VERSION 5.8 ;
BUSBITCHARS "[]" ;
DIVIDERCHAR "/" ;

PROPERTYDEFINITIONS
  MACRO filterSizeDrawingStyle STRING ;
  MACRO filterSize REAL ;
  MACRO segSnapMode STRING ;
  MACRO snapMode STRING ;
  MACRO ySnapSpacing REAL ;
  MACRO xSnapSpacing REAL ;
  MACRO gridMultiple INTEGER ;
  MACRO gridSpacing REAL ;
  MACRO stopLevel INTEGER ;
  MACRO startLevel INTEGER ;
  MACRO instLabel STRING ;
  MACRO arrayDisplay STRING ;
  MACRO pathCL STRING ;
END PROPERTYDEFINITIONS

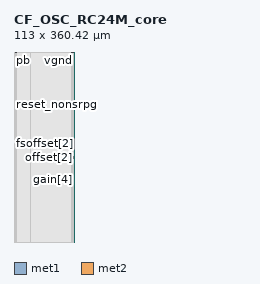
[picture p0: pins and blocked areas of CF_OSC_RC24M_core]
MACRO CF_OSC_RC24M_core
  ORIGIN 0 0 ;
  FOREIGN CF_OSC_RC24M_core 0 0 ;
  SIZE 113 BY 360.42 ;
  PIN reset_nonsrpg
    DIRECTION INPUT ;
    USE SIGNAL ;
    PORT
      LAYER met1 ;
        RECT 112.89 261.655 112.975 261.765 ;
    END
  END reset_nonsrpg
  PIN pb
    DIRECTION OUTPUT ;
    USE SIGNAL ;
    PORT
      LAYER met2 ;
        RECT 2.29 360.31 2.63 360.42 ;
    END
  END pb
  PIN fsoffset[2]
    DIRECTION INOUT ;
    USE SIGNAL ;
    PORT
      LAYER met1 ;
        RECT 112.715 172.265 112.835 172.385 ;
    END
  END fsoffset[2]
  PIN fs[0]
    DIRECTION INOUT ;
    USE SIGNAL ;
    PORT
      LAYER met1 ;
        RECT 112.715 156.35 112.835 156.47 ;
    END
  END fs[0]
  PIN fs[1]
    DIRECTION INOUT ;
    USE SIGNAL ;
    PORT
      LAYER met1 ;
        RECT 112.685 157.09 112.805 157.21 ;
    END
  END fs[1]
  PIN fs[2]
    DIRECTION INOUT ;
    USE SIGNAL ;
    PORT
      LAYER met1 ;
        RECT 112.695 158.24 112.815 158.36 ;
    END
  END fs[2]
  PIN offset[1]
    DIRECTION INOUT ;
    USE SIGNAL ;
    PORT
      LAYER met1 ;
        RECT 112.715 159.31 112.835 159.43 ;
    END
  END offset[1]
  PIN offset[2]
    DIRECTION INOUT ;
    USE SIGNAL ;
    PORT
      LAYER met1 ;
        RECT 112.715 160.05 112.835 160.17 ;
    END
  END offset[2]
  PIN offset[3]
    DIRECTION INOUT ;
    USE SIGNAL ;
    PORT
      LAYER met1 ;
        RECT 112.695 161.16 112.815 161.28 ;
    END
  END offset[3]
  PIN offset[4]
    DIRECTION INOUT ;
    USE SIGNAL ;
    PORT
      LAYER met1 ;
        RECT 112.69 161.9 112.81 162.02 ;
    END
  END offset[4]
  PIN offset[5]
    DIRECTION INOUT ;
    USE SIGNAL ;
    PORT
      LAYER met1 ;
        RECT 112.74 163.01 112.86 163.13 ;
    END
  END offset[5]
  PIN offset[6]
    DIRECTION INOUT ;
    USE SIGNAL ;
    PORT
      LAYER met1 ;
        RECT 112.715 164.12 112.835 164.24 ;
    END
  END offset[6]
  PIN offset[7]
    DIRECTION INOUT ;
    USE SIGNAL ;
    PORT
      LAYER met1 ;
        RECT 112.685 164.86 112.805 164.98 ;
    END
  END offset[7]
  PIN usb_off
    DIRECTION INOUT ;
    USE SIGNAL ;
    PORT
      LAYER met1 ;
        RECT 112.69 165.97 112.81 166.09 ;
    END
  END usb_off
  PIN fsoffset[0]
    DIRECTION INOUT ;
    USE SIGNAL ;
    PORT
      LAYER met1 ;
        RECT 112.74 166.71 112.86 166.83 ;
    END
  END fsoffset[0]
  PIN fsoffset[1]
    DIRECTION INOUT ;
    USE SIGNAL ;
    PORT
      LAYER met1 ;
        RECT 112.73 167.82 112.85 167.94 ;
    END
  END fsoffset[1]
  PIN gain[5]
    DIRECTION INOUT ;
    USE SIGNAL ;
    PORT
      LAYER met1 ;
        RECT 112.71 133.03 112.83 133.15 ;
    END
  END gain[5]
  PIN gain[4]
    DIRECTION INOUT ;
    USE SIGNAL ;
    PORT
      LAYER met1 ;
        RECT 112.705 133.52 112.825 133.64 ;
    END
  END gain[4]
  PIN gain[3]
    DIRECTION INOUT ;
    USE SIGNAL ;
    PORT
      LAYER met1 ;
        RECT 112.71 134.01 112.83 134.13 ;
    END
  END gain[3]
  PIN gain[2]
    DIRECTION INOUT ;
    USE SIGNAL ;
    PORT
      LAYER met1 ;
        RECT 112.7 134.505 112.82 134.625 ;
    END
  END gain[2]
  PIN gain[1]
    DIRECTION INOUT ;
    USE SIGNAL ;
    PORT
      LAYER met1 ;
        RECT 112.725 134.99 112.845 135.11 ;
    END
  END gain[1]
  PIN gain[0]
    DIRECTION INOUT ;
    USE SIGNAL ;
    PORT
      LAYER met1 ;
        RECT 112.695 135.475 112.815 135.595 ;
    END
  END gain[0]
  PIN offset[0]
    DIRECTION INOUT ;
    USE SIGNAL ;
    PORT
      LAYER met1 ;
        RECT 112.7 135.975 112.82 136.095 ;
    END
  END offset[0]
  PIN iout
    DIRECTION OUTPUT ;
    USE SIGNAL ;
    PORT
      LAYER met2 ;
        RECT 30.62 178.045 30.755 178.765 ;
    END
  END iout
  PIN reset
    DIRECTION INOUT ;
    USE SIGNAL ;
    PORT
      LAYER met1 ;
        RECT 112.68 256.825 112.83 256.975 ;
    END
  END reset
  PIN clk_ext_en
    DIRECTION INOUT ;
    USE SIGNAL ;
    PORT
      LAYER met1 ;
        RECT 112.69 257.625 112.84 257.775 ;
    END
  END clk_ext_en
  PIN clkout
    DIRECTION INOUT ;
    USE SIGNAL ;
    PORT
      LAYER met1 ;
        RECT 112.67 258.025 112.82 258.175 ;
    END
  END clkout
  PIN clk_ext
    DIRECTION INOUT ;
    USE SIGNAL ;
    PORT
      LAYER met1 ;
        RECT 112.7 257.225 112.85 257.375 ;
    END
  END clk_ext
  PIN clk_2x_en
    DIRECTION INOUT ;
    USE SIGNAL ;
    PORT
      LAYER met1 ;
        RECT 112.685 262.66 112.835 262.81 ;
    END
  END clk_2x_en
  PIN clk2xout
    DIRECTION INOUT ;
    USE SIGNAL ;
    PORT
      LAYER met1 ;
        RECT 112.68 260.6 112.83 260.75 ;
    END
  END clk2xout
  PIN iclkout
    DIRECTION INOUT ;
    USE SIGNAL ;
    PORT
      LAYER met1 ;
        RECT 112.675 260.24 112.825 260.39 ;
    END
  END iclkout
  PIN vref1
    DIRECTION INOUT ;
    USE SIGNAL ;
    PORT
      LAYER met1 ;
        RECT 112.665 259.365 112.815 259.515 ;
    END
  END vref1
  PIN usb_off_dly_out
    DIRECTION INOUT ;
    USE SIGNAL ;
    PORT
      LAYER met1 ;
        RECT 112.66 258.445 112.81 258.595 ;
    END
  END usb_off_dly_out
  PIN vnb
    DIRECTION INOUT ;
    USE SIGNAL ;
    PORT
      LAYER met1 ;
        RECT 112.675 256.375 112.875 256.575 ;
    END
  END vnb
  PIN usb_off_dly_in
    DIRECTION INOUT ;
    USE SIGNAL ;
    PORT
      LAYER met1 ;
        RECT 112.735 177.965 112.875 178.115 ;
    END
  END usb_off_dly_in
  PIN pd
    DIRECTION INOUT ;
    USE SIGNAL ;
    PORT
      LAYER met1 ;
        RECT 112.72 173 112.84 173.12 ;
    END
  END pd
  PIN vpwr
    DIRECTION INOUT ;
    USE SIGNAL ;
    PORT
      LAYER met2 ;
        RECT 110.985 359.4 112.985 360.42 ;
    END
  END vpwr
  PIN vgnd
    DIRECTION INOUT ;
    USE SIGNAL ;
    PORT
      LAYER met2 ;
        RECT 109.045 359.425 110.685 360.42 ;
    END
  END vgnd
  PIN iref
    DIRECTION INOUT ;
    USE SIGNAL ;
    PORT
      LAYER met2 ;
        RECT 3.755 360.28 4.075 360.42 ;
    END
  END iref
  PIN vpb
    DIRECTION INOUT ;
    USE SIGNAL ;
    PORT
      LAYER met1 ;
        RECT 112.66 255.97 112.81 256.12 ;
    END
  END vpb
  PROPERTY filterSizeDrawingStyle "empty" ;
  PROPERTY filterSize 3 ;
  PROPERTY segSnapMode "orthogonal" ;
  PROPERTY snapMode "orthogonal" ;
  PROPERTY ySnapSpacing 0.005 ;
  PROPERTY xSnapSpacing 0.005 ;
  PROPERTY gridMultiple 5 ;
  PROPERTY gridSpacing 0.025 ;
  PROPERTY stopLevel 21 ;
  PROPERTY startLevel 0 ;
  PROPERTY instLabel "master" ;
  PROPERTY arrayDisplay "Full" ;
  PROPERTY pathCL "yes" ;
  OBS
    LAYER li1 ;
      RECT 0 0 113 360.42 ;
    LAYER met1 ;
      RECT 0 0 112.66 360.42 ;
      RECT 112.66 0 112.665 255.97 ;
      RECT 112.66 256.12 112.665 258.445 ;
      RECT 112.66 258.595 112.665 360.42 ;
      RECT 112.665 0 112.67 255.97 ;
      RECT 112.665 256.12 112.67 258.445 ;
      RECT 112.665 258.595 112.67 259.365 ;
      RECT 112.665 259.515 112.67 360.42 ;
      RECT 112.67 0 112.675 255.97 ;
      RECT 112.67 256.12 112.675 258.025 ;
      RECT 112.67 258.175 112.675 258.445 ;
      RECT 112.67 258.595 112.675 259.365 ;
      RECT 112.67 259.515 112.675 360.42 ;
      RECT 112.675 0 112.68 255.97 ;
      RECT 112.675 256.12 112.68 256.375 ;
      RECT 112.675 256.575 112.68 258.025 ;
      RECT 112.675 258.175 112.68 258.445 ;
      RECT 112.675 258.595 112.68 259.365 ;
      RECT 112.675 259.515 112.68 260.24 ;
      RECT 112.675 260.39 112.68 360.42 ;
      RECT 112.68 0 112.685 255.97 ;
      RECT 112.68 256.12 112.685 256.375 ;
      RECT 112.68 256.575 112.685 256.825 ;
      RECT 112.68 256.975 112.685 258.025 ;
      RECT 112.68 258.175 112.685 258.445 ;
      RECT 112.68 258.595 112.685 259.365 ;
      RECT 112.68 259.515 112.685 260.24 ;
      RECT 112.68 260.39 112.685 260.6 ;
      RECT 112.68 260.75 112.685 360.42 ;
      RECT 112.685 0 112.69 157.09 ;
      RECT 112.685 157.21 112.69 164.86 ;
      RECT 112.685 164.98 112.69 255.97 ;
      RECT 112.685 256.12 112.69 256.375 ;
      RECT 112.685 256.575 112.69 256.825 ;
      RECT 112.685 256.975 112.69 258.025 ;
      RECT 112.685 258.175 112.69 258.445 ;
      RECT 112.685 258.595 112.69 259.365 ;
      RECT 112.685 259.515 112.69 260.24 ;
      RECT 112.685 260.39 112.69 260.6 ;
      RECT 112.685 260.75 112.69 262.66 ;
      RECT 112.685 262.81 112.69 360.42 ;
      RECT 112.69 0 112.695 157.09 ;
      RECT 112.69 157.21 112.695 161.9 ;
      RECT 112.69 162.02 112.695 164.86 ;
      RECT 112.69 164.98 112.695 165.97 ;
      RECT 112.69 166.09 112.695 255.97 ;
      RECT 112.69 256.12 112.695 256.375 ;
      RECT 112.69 256.575 112.695 256.825 ;
      RECT 112.69 256.975 112.695 257.625 ;
      RECT 112.69 257.775 112.695 258.025 ;
      RECT 112.69 258.175 112.695 258.445 ;
      RECT 112.69 258.595 112.695 259.365 ;
      RECT 112.69 259.515 112.695 260.24 ;
      RECT 112.69 260.39 112.695 260.6 ;
      RECT 112.69 260.75 112.695 262.66 ;
      RECT 112.69 262.81 112.695 360.42 ;
      RECT 112.695 0 112.7 135.475 ;
      RECT 112.695 135.595 112.7 157.09 ;
      RECT 112.695 157.21 112.7 158.24 ;
      RECT 112.695 158.36 112.7 161.16 ;
      RECT 112.695 161.28 112.7 161.9 ;
      RECT 112.695 162.02 112.7 164.86 ;
      RECT 112.695 164.98 112.7 165.97 ;
      RECT 112.695 166.09 112.7 255.97 ;
      RECT 112.695 256.12 112.7 256.375 ;
      RECT 112.695 256.575 112.7 256.825 ;
      RECT 112.695 256.975 112.7 257.625 ;
      RECT 112.695 257.775 112.7 258.025 ;
      RECT 112.695 258.175 112.7 258.445 ;
      RECT 112.695 258.595 112.7 259.365 ;
      RECT 112.695 259.515 112.7 260.24 ;
      RECT 112.695 260.39 112.7 260.6 ;
      RECT 112.695 260.75 112.7 262.66 ;
      RECT 112.695 262.81 112.7 360.42 ;
      RECT 112.7 0 112.705 134.505 ;
      RECT 112.7 134.625 112.705 135.475 ;
      RECT 112.7 135.595 112.705 135.975 ;
      RECT 112.7 136.095 112.705 157.09 ;
      RECT 112.7 157.21 112.705 158.24 ;
      RECT 112.7 158.36 112.705 161.16 ;
      RECT 112.7 161.28 112.705 161.9 ;
      RECT 112.7 162.02 112.705 164.86 ;
      RECT 112.7 164.98 112.705 165.97 ;
      RECT 112.7 166.09 112.705 255.97 ;
      RECT 112.7 256.12 112.705 256.375 ;
      RECT 112.7 256.575 112.705 256.825 ;
      RECT 112.7 256.975 112.705 257.225 ;
      RECT 112.7 257.375 112.705 257.625 ;
      RECT 112.7 257.775 112.705 258.025 ;
      RECT 112.7 258.175 112.705 258.445 ;
      RECT 112.7 258.595 112.705 259.365 ;
      RECT 112.7 259.515 112.705 260.24 ;
      RECT 112.7 260.39 112.705 260.6 ;
      RECT 112.7 260.75 112.705 262.66 ;
      RECT 112.7 262.81 112.705 360.42 ;
      RECT 112.705 0 112.71 133.52 ;
      RECT 112.705 133.64 112.71 134.505 ;
      RECT 112.705 134.625 112.71 135.475 ;
      RECT 112.705 135.595 112.71 135.975 ;
      RECT 112.705 136.095 112.71 157.09 ;
      RECT 112.705 157.21 112.71 158.24 ;
      RECT 112.705 158.36 112.71 161.16 ;
      RECT 112.705 161.28 112.71 161.9 ;
      RECT 112.705 162.02 112.71 164.86 ;
      RECT 112.705 164.98 112.71 165.97 ;
      RECT 112.705 166.09 112.71 255.97 ;
      RECT 112.705 256.12 112.71 256.375 ;
      RECT 112.705 256.575 112.71 256.825 ;
      RECT 112.705 256.975 112.71 257.225 ;
      RECT 112.705 257.375 112.71 257.625 ;
      RECT 112.705 257.775 112.71 258.025 ;
      RECT 112.705 258.175 112.71 258.445 ;
      RECT 112.705 258.595 112.71 259.365 ;
      RECT 112.705 259.515 112.71 260.24 ;
      RECT 112.705 260.39 112.71 260.6 ;
      RECT 112.705 260.75 112.71 262.66 ;
      RECT 112.705 262.81 112.71 360.42 ;
      RECT 112.71 0 112.715 133.03 ;
      RECT 112.71 133.15 112.715 133.52 ;
      RECT 112.71 133.64 112.715 134.01 ;
      RECT 112.71 134.13 112.715 134.505 ;
      RECT 112.71 134.625 112.715 135.475 ;
      RECT 112.71 135.595 112.715 135.975 ;
      RECT 112.71 136.095 112.715 157.09 ;
      RECT 112.71 157.21 112.715 158.24 ;
      RECT 112.71 158.36 112.715 161.16 ;
      RECT 112.71 161.28 112.715 161.9 ;
      RECT 112.71 162.02 112.715 164.86 ;
      RECT 112.71 164.98 112.715 165.97 ;
      RECT 112.71 166.09 112.715 255.97 ;
      RECT 112.71 256.12 112.715 256.375 ;
      RECT 112.71 256.575 112.715 256.825 ;
      RECT 112.71 256.975 112.715 257.225 ;
      RECT 112.71 257.375 112.715 257.625 ;
      RECT 112.71 257.775 112.715 258.025 ;
      RECT 112.71 258.175 112.715 258.445 ;
      RECT 112.71 258.595 112.715 259.365 ;
      RECT 112.71 259.515 112.715 260.24 ;
      RECT 112.71 260.39 112.715 260.6 ;
      RECT 112.71 260.75 112.715 262.66 ;
      RECT 112.71 262.81 112.715 360.42 ;
      RECT 112.715 0 112.72 133.03 ;
      RECT 112.715 133.15 112.72 133.52 ;
      RECT 112.715 133.64 112.72 134.01 ;
      RECT 112.715 134.13 112.72 134.505 ;
      RECT 112.715 134.625 112.72 135.475 ;
      RECT 112.715 135.595 112.72 135.975 ;
      RECT 112.715 136.095 112.72 156.35 ;
      RECT 112.715 156.47 112.72 157.09 ;
      RECT 112.715 157.21 112.72 158.24 ;
      RECT 112.715 158.36 112.72 159.31 ;
      RECT 112.715 159.43 112.72 160.05 ;
      RECT 112.715 160.17 112.72 161.16 ;
      RECT 112.715 161.28 112.72 161.9 ;
      RECT 112.715 162.02 112.72 164.12 ;
      RECT 112.715 164.24 112.72 164.86 ;
      RECT 112.715 164.98 112.72 165.97 ;
      RECT 112.715 166.09 112.72 172.265 ;
      RECT 112.715 172.385 112.72 255.97 ;
      RECT 112.715 256.12 112.72 256.375 ;
      RECT 112.715 256.575 112.72 256.825 ;
      RECT 112.715 256.975 112.72 257.225 ;
      RECT 112.715 257.375 112.72 257.625 ;
      RECT 112.715 257.775 112.72 258.025 ;
      RECT 112.715 258.175 112.72 258.445 ;
      RECT 112.715 258.595 112.72 259.365 ;
      RECT 112.715 259.515 112.72 260.24 ;
      RECT 112.715 260.39 112.72 260.6 ;
      RECT 112.715 260.75 112.72 262.66 ;
      RECT 112.715 262.81 112.72 360.42 ;
      RECT 112.72 0 112.725 133.03 ;
      RECT 112.72 133.15 112.725 133.52 ;
      RECT 112.72 133.64 112.725 134.01 ;
      RECT 112.72 134.13 112.725 134.505 ;
      RECT 112.72 134.625 112.725 135.475 ;
      RECT 112.72 135.595 112.725 135.975 ;
      RECT 112.72 136.095 112.725 156.35 ;
      RECT 112.72 156.47 112.725 157.09 ;
      RECT 112.72 157.21 112.725 158.24 ;
      RECT 112.72 158.36 112.725 159.31 ;
      RECT 112.72 159.43 112.725 160.05 ;
      RECT 112.72 160.17 112.725 161.16 ;
      RECT 112.72 161.28 112.725 161.9 ;
      RECT 112.72 162.02 112.725 164.12 ;
      RECT 112.72 164.24 112.725 164.86 ;
      RECT 112.72 164.98 112.725 165.97 ;
      RECT 112.72 166.09 112.725 172.265 ;
      RECT 112.72 172.385 112.725 173 ;
      RECT 112.72 173.12 112.725 255.97 ;
      RECT 112.72 256.12 112.725 256.375 ;
      RECT 112.72 256.575 112.725 256.825 ;
      RECT 112.72 256.975 112.725 257.225 ;
      RECT 112.72 257.375 112.725 257.625 ;
      RECT 112.72 257.775 112.725 258.025 ;
      RECT 112.72 258.175 112.725 258.445 ;
      RECT 112.72 258.595 112.725 259.365 ;
      RECT 112.72 259.515 112.725 260.24 ;
      RECT 112.72 260.39 112.725 260.6 ;
      RECT 112.72 260.75 112.725 262.66 ;
      RECT 112.72 262.81 112.725 360.42 ;
      RECT 112.725 0 112.73 133.03 ;
      RECT 112.725 133.15 112.73 133.52 ;
      RECT 112.725 133.64 112.73 134.01 ;
      RECT 112.725 134.13 112.73 134.505 ;
      RECT 112.725 134.625 112.73 134.99 ;
      RECT 112.725 135.11 112.73 135.475 ;
      RECT 112.725 135.595 112.73 135.975 ;
      RECT 112.725 136.095 112.73 156.35 ;
      RECT 112.725 156.47 112.73 157.09 ;
      RECT 112.725 157.21 112.73 158.24 ;
      RECT 112.725 158.36 112.73 159.31 ;
      RECT 112.725 159.43 112.73 160.05 ;
      RECT 112.725 160.17 112.73 161.16 ;
      RECT 112.725 161.28 112.73 161.9 ;
      RECT 112.725 162.02 112.73 164.12 ;
      RECT 112.725 164.24 112.73 164.86 ;
      RECT 112.725 164.98 112.73 165.97 ;
      RECT 112.725 166.09 112.73 172.265 ;
      RECT 112.725 172.385 112.73 173 ;
      RECT 112.725 173.12 112.73 255.97 ;
      RECT 112.725 256.12 112.73 256.375 ;
      RECT 112.725 256.575 112.73 256.825 ;
      RECT 112.725 256.975 112.73 257.225 ;
      RECT 112.725 257.375 112.73 257.625 ;
      RECT 112.725 257.775 112.73 258.025 ;
      RECT 112.725 258.175 112.73 258.445 ;
      RECT 112.725 258.595 112.73 259.365 ;
      RECT 112.725 259.515 112.73 260.24 ;
      RECT 112.725 260.39 112.73 260.6 ;
      RECT 112.725 260.75 112.73 262.66 ;
      RECT 112.725 262.81 112.73 360.42 ;
      RECT 112.73 0 112.735 133.03 ;
      RECT 112.73 133.15 112.735 133.52 ;
      RECT 112.73 133.64 112.735 134.01 ;
      RECT 112.73 134.13 112.735 134.505 ;
      RECT 112.73 134.625 112.735 134.99 ;
      RECT 112.73 135.11 112.735 135.475 ;
      RECT 112.73 135.595 112.735 135.975 ;
      RECT 112.73 136.095 112.735 156.35 ;
      RECT 112.73 156.47 112.735 157.09 ;
      RECT 112.73 157.21 112.735 158.24 ;
      RECT 112.73 158.36 112.735 159.31 ;
      RECT 112.73 159.43 112.735 160.05 ;
      RECT 112.73 160.17 112.735 161.16 ;
      RECT 112.73 161.28 112.735 161.9 ;
      RECT 112.73 162.02 112.735 164.12 ;
      RECT 112.73 164.24 112.735 164.86 ;
      RECT 112.73 164.98 112.735 165.97 ;
      RECT 112.73 166.09 112.735 167.82 ;
      RECT 112.73 167.94 112.735 172.265 ;
      RECT 112.73 172.385 112.735 173 ;
      RECT 112.73 173.12 112.735 255.97 ;
      RECT 112.73 256.12 112.735 256.375 ;
      RECT 112.73 256.575 112.735 256.825 ;
      RECT 112.73 256.975 112.735 257.225 ;
      RECT 112.73 257.375 112.735 257.625 ;
      RECT 112.73 257.775 112.735 258.025 ;
      RECT 112.73 258.175 112.735 258.445 ;
      RECT 112.73 258.595 112.735 259.365 ;
      RECT 112.73 259.515 112.735 260.24 ;
      RECT 112.73 260.39 112.735 260.6 ;
      RECT 112.73 260.75 112.735 262.66 ;
      RECT 112.73 262.81 112.735 360.42 ;
      RECT 112.735 0 112.74 133.03 ;
      RECT 112.735 133.15 112.74 133.52 ;
      RECT 112.735 133.64 112.74 134.01 ;
      RECT 112.735 134.13 112.74 134.505 ;
      RECT 112.735 134.625 112.74 134.99 ;
      RECT 112.735 135.11 112.74 135.475 ;
      RECT 112.735 135.595 112.74 135.975 ;
      RECT 112.735 136.095 112.74 156.35 ;
      RECT 112.735 156.47 112.74 157.09 ;
      RECT 112.735 157.21 112.74 158.24 ;
      RECT 112.735 158.36 112.74 159.31 ;
      RECT 112.735 159.43 112.74 160.05 ;
      RECT 112.735 160.17 112.74 161.16 ;
      RECT 112.735 161.28 112.74 161.9 ;
      RECT 112.735 162.02 112.74 164.12 ;
      RECT 112.735 164.24 112.74 164.86 ;
      RECT 112.735 164.98 112.74 165.97 ;
      RECT 112.735 166.09 112.74 167.82 ;
      RECT 112.735 167.94 112.74 172.265 ;
      RECT 112.735 172.385 112.74 173 ;
      RECT 112.735 173.12 112.74 177.965 ;
      RECT 112.735 178.115 112.74 255.97 ;
      RECT 112.735 256.12 112.74 256.375 ;
      RECT 112.735 256.575 112.74 256.825 ;
      RECT 112.735 256.975 112.74 257.225 ;
      RECT 112.735 257.375 112.74 257.625 ;
      RECT 112.735 257.775 112.74 258.025 ;
      RECT 112.735 258.175 112.74 258.445 ;
      RECT 112.735 258.595 112.74 259.365 ;
      RECT 112.735 259.515 112.74 260.24 ;
      RECT 112.735 260.39 112.74 260.6 ;
      RECT 112.735 260.75 112.74 262.66 ;
      RECT 112.735 262.81 112.74 360.42 ;
      RECT 112.74 0 112.805 133.03 ;
      RECT 112.74 133.15 112.805 133.52 ;
      RECT 112.74 133.64 112.805 134.01 ;
      RECT 112.74 134.13 112.805 134.505 ;
      RECT 112.74 134.625 112.805 134.99 ;
      RECT 112.74 135.11 112.805 135.475 ;
      RECT 112.74 135.595 112.805 135.975 ;
      RECT 112.74 136.095 112.805 156.35 ;
      RECT 112.74 156.47 112.805 157.09 ;
      RECT 112.74 157.21 112.805 158.24 ;
      RECT 112.74 158.36 112.805 159.31 ;
      RECT 112.74 159.43 112.805 160.05 ;
      RECT 112.74 160.17 112.805 161.16 ;
      RECT 112.74 161.28 112.805 161.9 ;
      RECT 112.74 162.02 112.805 163.01 ;
      RECT 112.74 163.13 112.805 164.12 ;
      RECT 112.74 164.24 112.805 164.86 ;
      RECT 112.74 164.98 112.805 165.97 ;
      RECT 112.74 166.09 112.805 166.71 ;
      RECT 112.74 166.83 112.805 167.82 ;
      RECT 112.74 167.94 112.805 172.265 ;
      RECT 112.74 172.385 112.805 173 ;
      RECT 112.74 173.12 112.805 177.965 ;
      RECT 112.74 178.115 112.805 255.97 ;
      RECT 112.74 256.12 112.805 256.375 ;
      RECT 112.74 256.575 112.805 256.825 ;
      RECT 112.74 256.975 112.805 257.225 ;
      RECT 112.74 257.375 112.805 257.625 ;
      RECT 112.74 257.775 112.805 258.025 ;
      RECT 112.74 258.175 112.805 258.445 ;
      RECT 112.74 258.595 112.805 259.365 ;
      RECT 112.74 259.515 112.805 260.24 ;
      RECT 112.74 260.39 112.805 260.6 ;
      RECT 112.74 260.75 112.805 262.66 ;
      RECT 112.74 262.81 112.805 360.42 ;
      RECT 112.805 0 112.81 133.03 ;
      RECT 112.805 133.15 112.81 133.52 ;
      RECT 112.805 133.64 112.81 134.01 ;
      RECT 112.805 134.13 112.81 134.505 ;
      RECT 112.805 134.625 112.81 134.99 ;
      RECT 112.805 135.11 112.81 135.475 ;
      RECT 112.805 135.595 112.81 135.975 ;
      RECT 112.805 136.095 112.81 156.35 ;
      RECT 112.805 156.47 112.81 158.24 ;
      RECT 112.805 158.36 112.81 159.31 ;
      RECT 112.805 159.43 112.81 160.05 ;
      RECT 112.805 160.17 112.81 161.16 ;
      RECT 112.805 161.28 112.81 161.9 ;
      RECT 112.805 162.02 112.81 163.01 ;
      RECT 112.805 163.13 112.81 164.12 ;
      RECT 112.805 164.24 112.81 165.97 ;
      RECT 112.805 166.09 112.81 166.71 ;
      RECT 112.805 166.83 112.81 167.82 ;
      RECT 112.805 167.94 112.81 172.265 ;
      RECT 112.805 172.385 112.81 173 ;
      RECT 112.805 173.12 112.81 177.965 ;
      RECT 112.805 178.115 112.81 255.97 ;
      RECT 112.805 256.12 112.81 256.375 ;
      RECT 112.805 256.575 112.81 256.825 ;
      RECT 112.805 256.975 112.81 257.225 ;
      RECT 112.805 257.375 112.81 257.625 ;
      RECT 112.805 257.775 112.81 258.025 ;
      RECT 112.805 258.175 112.81 258.445 ;
      RECT 112.805 258.595 112.81 259.365 ;
      RECT 112.805 259.515 112.81 260.24 ;
      RECT 112.805 260.39 112.81 260.6 ;
      RECT 112.805 260.75 112.81 262.66 ;
      RECT 112.805 262.81 112.81 360.42 ;
      RECT 112.81 0 112.815 133.03 ;
      RECT 112.81 133.15 112.815 133.52 ;
      RECT 112.81 133.64 112.815 134.01 ;
      RECT 112.81 134.13 112.815 134.505 ;
      RECT 112.81 134.625 112.815 134.99 ;
      RECT 112.81 135.11 112.815 135.475 ;
      RECT 112.81 135.595 112.815 135.975 ;
      RECT 112.81 136.095 112.815 156.35 ;
      RECT 112.81 156.47 112.815 158.24 ;
      RECT 112.81 158.36 112.815 159.31 ;
      RECT 112.81 159.43 112.815 160.05 ;
      RECT 112.81 160.17 112.815 161.16 ;
      RECT 112.81 161.28 112.815 163.01 ;
      RECT 112.81 163.13 112.815 164.12 ;
      RECT 112.81 164.24 112.815 166.71 ;
      RECT 112.81 166.83 112.815 167.82 ;
      RECT 112.81 167.94 112.815 172.265 ;
      RECT 112.81 172.385 112.815 173 ;
      RECT 112.81 173.12 112.815 177.965 ;
      RECT 112.81 178.115 112.815 256.375 ;
      RECT 112.81 256.575 112.815 256.825 ;
      RECT 112.81 256.975 112.815 257.225 ;
      RECT 112.81 257.375 112.815 257.625 ;
      RECT 112.81 257.775 112.815 258.025 ;
      RECT 112.81 258.175 112.815 259.365 ;
      RECT 112.81 259.515 112.815 260.24 ;
      RECT 112.81 260.39 112.815 260.6 ;
      RECT 112.81 260.75 112.815 262.66 ;
      RECT 112.81 262.81 112.815 360.42 ;
      RECT 112.815 0 112.82 133.03 ;
      RECT 112.815 133.15 112.82 133.52 ;
      RECT 112.815 133.64 112.82 134.01 ;
      RECT 112.815 134.13 112.82 134.505 ;
      RECT 112.815 134.625 112.82 134.99 ;
      RECT 112.815 135.11 112.82 135.975 ;
      RECT 112.815 136.095 112.82 156.35 ;
      RECT 112.815 156.47 112.82 159.31 ;
      RECT 112.815 159.43 112.82 160.05 ;
      RECT 112.815 160.17 112.82 163.01 ;
      RECT 112.815 163.13 112.82 164.12 ;
      RECT 112.815 164.24 112.82 166.71 ;
      RECT 112.815 166.83 112.82 167.82 ;
      RECT 112.815 167.94 112.82 172.265 ;
      RECT 112.815 172.385 112.82 173 ;
      RECT 112.815 173.12 112.82 177.965 ;
      RECT 112.815 178.115 112.82 256.375 ;
      RECT 112.815 256.575 112.82 256.825 ;
      RECT 112.815 256.975 112.82 257.225 ;
      RECT 112.815 257.375 112.82 257.625 ;
      RECT 112.815 257.775 112.82 258.025 ;
      RECT 112.815 258.175 112.82 260.24 ;
      RECT 112.815 260.39 112.82 260.6 ;
      RECT 112.815 260.75 112.82 262.66 ;
      RECT 112.815 262.81 112.82 360.42 ;
      RECT 112.82 0 112.825 133.03 ;
      RECT 112.82 133.15 112.825 133.52 ;
      RECT 112.82 133.64 112.825 134.01 ;
      RECT 112.82 134.13 112.825 134.99 ;
      RECT 112.82 135.11 112.825 156.35 ;
      RECT 112.82 156.47 112.825 159.31 ;
      RECT 112.82 159.43 112.825 160.05 ;
      RECT 112.82 160.17 112.825 163.01 ;
      RECT 112.82 163.13 112.825 164.12 ;
      RECT 112.82 164.24 112.825 166.71 ;
      RECT 112.82 166.83 112.825 167.82 ;
      RECT 112.82 167.94 112.825 172.265 ;
      RECT 112.82 172.385 112.825 173 ;
      RECT 112.82 173.12 112.825 177.965 ;
      RECT 112.82 178.115 112.825 256.375 ;
      RECT 112.82 256.575 112.825 256.825 ;
      RECT 112.82 256.975 112.825 257.225 ;
      RECT 112.82 257.375 112.825 257.625 ;
      RECT 112.82 257.775 112.825 260.24 ;
      RECT 112.82 260.39 112.825 260.6 ;
      RECT 112.82 260.75 112.825 262.66 ;
      RECT 112.82 262.81 112.825 360.42 ;
      RECT 112.825 0 112.83 133.03 ;
      RECT 112.825 133.15 112.83 134.01 ;
      RECT 112.825 134.13 112.83 134.99 ;
      RECT 112.825 135.11 112.83 156.35 ;
      RECT 112.825 156.47 112.83 159.31 ;
      RECT 112.825 159.43 112.83 160.05 ;
      RECT 112.825 160.17 112.83 163.01 ;
      RECT 112.825 163.13 112.83 164.12 ;
      RECT 112.825 164.24 112.83 166.71 ;
      RECT 112.825 166.83 112.83 167.82 ;
      RECT 112.825 167.94 112.83 172.265 ;
      RECT 112.825 172.385 112.83 173 ;
      RECT 112.825 173.12 112.83 177.965 ;
      RECT 112.825 178.115 112.83 256.375 ;
      RECT 112.825 256.575 112.83 256.825 ;
      RECT 112.825 256.975 112.83 257.225 ;
      RECT 112.825 257.375 112.83 257.625 ;
      RECT 112.825 257.775 112.83 260.6 ;
      RECT 112.825 260.75 112.83 262.66 ;
      RECT 112.825 262.81 112.83 360.42 ;
      RECT 112.83 0 112.835 134.99 ;
      RECT 112.83 135.11 112.835 156.35 ;
      RECT 112.83 156.47 112.835 159.31 ;
      RECT 112.83 159.43 112.835 160.05 ;
      RECT 112.83 160.17 112.835 163.01 ;
      RECT 112.83 163.13 112.835 164.12 ;
      RECT 112.83 164.24 112.835 166.71 ;
      RECT 112.83 166.83 112.835 167.82 ;
      RECT 112.83 167.94 112.835 172.265 ;
      RECT 112.83 172.385 112.835 173 ;
      RECT 112.83 173.12 112.835 177.965 ;
      RECT 112.83 178.115 112.835 256.375 ;
      RECT 112.83 256.575 112.835 257.225 ;
      RECT 112.83 257.375 112.835 257.625 ;
      RECT 112.83 257.775 112.835 262.66 ;
      RECT 112.83 262.81 112.835 360.42 ;
      RECT 112.835 0 112.84 134.99 ;
      RECT 112.835 135.11 112.84 163.01 ;
      RECT 112.835 163.13 112.84 166.71 ;
      RECT 112.835 166.83 112.84 167.82 ;
      RECT 112.835 167.94 112.84 173 ;
      RECT 112.835 173.12 112.84 177.965 ;
      RECT 112.835 178.115 112.84 256.375 ;
      RECT 112.835 256.575 112.84 257.225 ;
      RECT 112.835 257.375 112.84 257.625 ;
      RECT 112.835 257.775 112.84 360.42 ;
      RECT 112.84 0 112.845 134.99 ;
      RECT 112.84 135.11 112.845 163.01 ;
      RECT 112.84 163.13 112.845 166.71 ;
      RECT 112.84 166.83 112.845 167.82 ;
      RECT 112.84 167.94 112.845 177.965 ;
      RECT 112.84 178.115 112.845 256.375 ;
      RECT 112.84 256.575 112.845 257.225 ;
      RECT 112.84 257.375 112.845 360.42 ;
      RECT 112.845 0 112.85 163.01 ;
      RECT 112.845 163.13 112.85 166.71 ;
      RECT 112.845 166.83 112.85 167.82 ;
      RECT 112.845 167.94 112.85 177.965 ;
      RECT 112.845 178.115 112.85 256.375 ;
      RECT 112.845 256.575 112.85 257.225 ;
      RECT 112.845 257.375 112.85 360.42 ;
      RECT 112.85 0 112.86 163.01 ;
      RECT 112.85 163.13 112.86 166.71 ;
      RECT 112.85 166.83 112.86 177.965 ;
      RECT 112.85 178.115 112.86 256.375 ;
      RECT 112.85 256.575 112.86 360.42 ;
      RECT 112.86 0 112.875 177.965 ;
      RECT 112.86 178.115 112.875 256.375 ;
      RECT 112.86 256.575 112.875 360.42 ;
      RECT 112.875 0 112.89 360.42 ;
      RECT 112.89 0 112.975 261.655 ;
      RECT 112.89 261.765 112.975 360.42 ;
      RECT 112.975 0 113 360.42 ;
    LAYER met2 ;
      RECT 0 0 2.29 360.42 ;
      RECT 2.29 0 2.63 360.31 ;
      RECT 2.63 0 3.755 360.42 ;
      RECT 3.755 0 4.075 360.28 ;
      RECT 4.075 0 30.62 360.42 ;
      RECT 30.62 0 30.755 178.045 ;
      RECT 30.62 178.765 30.755 360.42 ;
      RECT 30.755 0 109.045 360.42 ;
      RECT 109.045 0 110.685 359.425 ;
      RECT 110.685 0 110.985 360.42 ;
      RECT 110.985 0 112.985 359.4 ;
      RECT 112.985 0 113 360.42 ;
  END
END CF_OSC_RC24M_core

END LIBRARY
